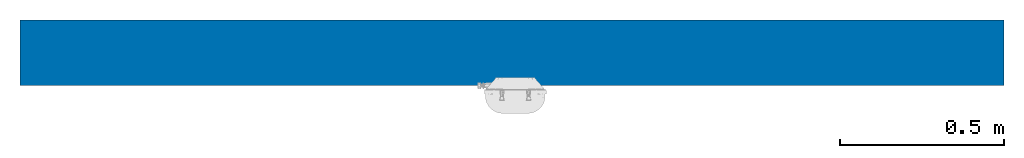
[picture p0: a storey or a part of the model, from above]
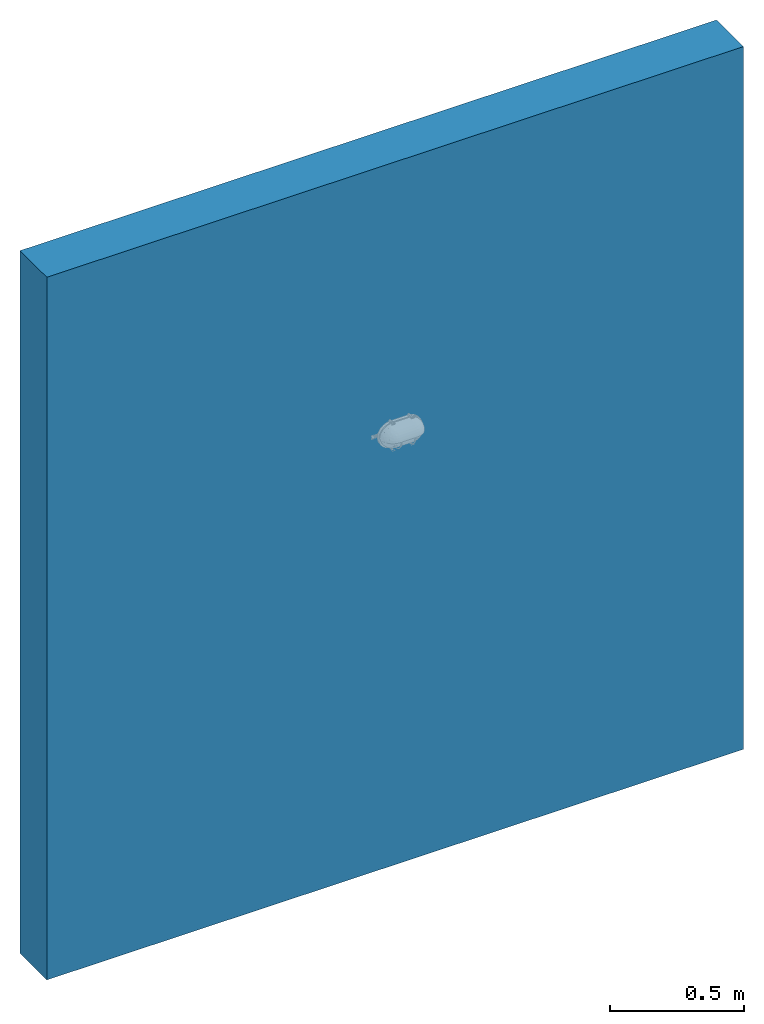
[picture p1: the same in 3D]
Properties of the parts of a building model (IFC2X3)

# File
Description: ViewDefinition [CoordinationView_V2.0], RevitIdentifiers [ContentGUID: 859801ba-2aed-4c05-8f14-c23a8034d926, VersionGUID: fbfc749f-8ba6-4628-a8b7-52c805de54c4, NumberOfSaves: 0], CoordinateReference [CoordinateBase: Shared Coordinates]
File name: Project1.ifc
Time: 2026-02-08T13:27:32+03:30
Written by: ODA SDAI 24.12
Made in: Autodesk Revit 25.4.0.32 (ENU) - IFC 25.4.0.32

# IfcProject, Project Number
LongName: home desing; Phase: Project Status

# IfcSite, Default
RefLatitude: 42, 21, 30, 344238; RefLongitude: -71, -3, -35, -194702; RefElevation: 0 m

# IfcBuilding
Pset_BuildingCommon - NumberOfStoreys: 1

# IfcBuildingStorey: Level:8mm Head (5)
Pset_AirSideSystemInformation - sets with these values: 2
Name | LongName = Name | Elevation (m)
Level 1 | Level 1 | 0
Level 2 | Level 2 | 3.2
Level 3 | Level 3 | 6.4
Level 4 | Level 4 | 9.6
Level 5 | Level 5 | 12.8

# IfcDistributionPort, Port_204264_1
Description: Flow; FlowDirection: SOURCEANDSINK

# IfcFlowTerminal: 5-palaemon-bulkhead:Variant 1 - Raw Brass, 5-palaemon-bulkhead:Variant 1 - Raw Brass:204264
In: Level 1
Type - Material: Raw Brass, Mat-Glass, Mat-Lamp holder, Mat-Lamp
Type - Pset_ManufacturerTypeInformation - Manufacturer: Lampfix
Pset_DistributionFlowElementCommon - Reference: Variant 1 - Raw Brass; sets with these values: 2

# IfcWallStandardCase: Basic Wall:Wall 20cm2, Basic Wall:Wall 20cm2:202089
In: Level 1
Type - PredefinedType: STANDARD; Material: Default Wall 0.2 m
Pset_QuantityTakeOff - Reference: Wall 20cm2; sets with these values: 2
Pset_WallCommon - Reference: Wall 20cm2; IsExternal: yes; ExtendToStructure: no; LoadBearing: no
